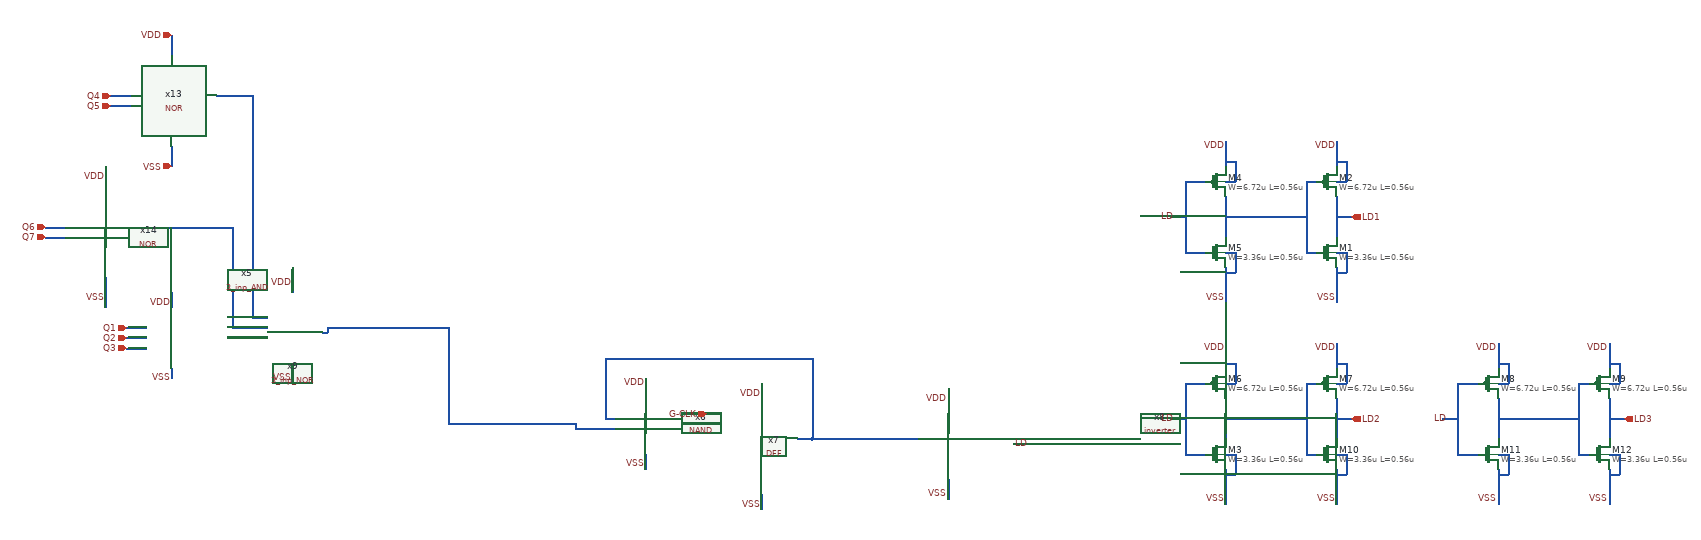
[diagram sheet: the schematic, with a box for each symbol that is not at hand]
v {xschem version=3.1.0 file_version=1.2
}
G {}
K {}
V {}
S {}
E {}
N 2390 1320 2430 1320 {
lab=LD}
N 630 1090 670 1090 {
lab=Q1}
N 1520 1290 1600 1290 {
lab=#net1}
N 1990 1150 1990 1310 {
lab=#net2}
N 1580 1150 1580 1270 {
lab=#net2}
N 1580 1270 1600 1270 {
lab=#net2}
N 1990 1310 2050 1310 {
lab=#net2}
N 1890 1200 1890 1230 {
lab=VDD}
N 1660 1190 1660 1220 {
lab=VDD}
N 1660 1340 1660 1370 {
lab=VSS}
N 1890 1420 1890 1450 {
lab=VSS}
N 1780 1260 1810 1260 {
lab=G-CLK}
N 1320 1280 1510 1280 {
lab=#net1}
N 1520 1280 1520 1290 {
lab=#net1}
N 1510 1280 1520 1280 {
lab=#net1}
N 2050 1310 2200 1310 {
lab=#net2}
N 1730 1280 1810 1280 {
lab=#net3}
N 720 1020 720 1050 {
lab=VDD}
N 720 1170 720 1190 {
lab=VSS}
N 630 1110 670 1110 {
lab=Q2}
N 840 1090 910 1090 {
lab=#net4}
N 680 890 710 890 {
lab=#net4}
N 1270 1110 1270 1280 {
lab=#net1}
N 1270 1280 1320 1280 {
lab=#net1}
N 630 1130 670 1130 {
lab=Q3}
N 1960 1310 1990 1310 {
lab=#net2}
N 1580 1150 1990 1150 {
lab=#net2}
N 2260 1210 2260 1250 {
lab=VDD}
N 2260 1390 2260 1430 {
lab=VSS}
N 1030 1090 1270 1090 {
lab=#net1}
N 1270 1090 1270 1110 {
lab=#net1}
N 1020 1100 1030 1100 {
lab=#net1}
N 1030 1090 1030 1100 {
lab=#net1}
N 880 1070 910 1070 {
lab=#net5}
N 880 630 880 1070 {
lab=#net5}
N 810 630 880 630 {
lab=#net5}
N 960 970 960 1020 {
lab=VDD}
N 960 1160 960 1200 {
lab=VSS}
N 590 770 590 810 {
lab=VDD}
N 590 990 590 1050 {
lab=VSS}
N 720 510 720 550 {
lab=VDD}
N 600 630 640 630 {
lab=Q4}
N 600 650 640 650 {
lab=Q5}
N 720 730 720 770 {
lab=VSS}
N 470 890 510 890 {
lab=Q6}
N 470 910 510 910 {
lab=Q7}
N 2730 800 2730 940 {
lab=LD}
N 2730 940 2770 940 {
lab=LD}
N 2730 800 2770 800 {
lab=LD}
N 2810 830 2810 910 {
lab=#net6}
N 2810 970 2810 1000 {
lab=VSS}
N 2810 740 2810 770 {
lab=VDD}
N 2810 870 2840 870 {
lab=#net6}
N 2700 870 2730 870 {
lab=LD}
N 2810 800 2830 800 {
lab=VDD}
N 2830 760 2830 800 {
lab=VDD}
N 2810 760 2830 760 {
lab=VDD}
N 2810 940 2830 940 {
lab=VSS}
N 2830 940 2830 980 {
lab=VSS}
N 2810 980 2830 980 {
lab=VSS}
N 2810 720 2810 740 {
lab=VDD}
N 2810 1000 2810 1040 {
lab=VSS}
N 3030 830 3030 910 {
lab=LD1}
N 3030 970 3030 1000 {
lab=VSS}
N 3030 740 3030 770 {
lab=VDD}
N 3030 870 3060 870 {
lab=LD1}
N 3030 800 3050 800 {
lab=VDD}
N 3050 760 3050 800 {
lab=VDD}
N 3030 760 3050 760 {
lab=VDD}
N 3030 940 3050 940 {
lab=VSS}
N 3050 940 3050 980 {
lab=VSS}
N 3030 980 3050 980 {
lab=VSS}
N 3030 720 3030 740 {
lab=VDD}
N 3030 1000 3030 1040 {
lab=VSS}
N 2970 800 2990 800 {
lab=#net6}
N 2970 800 2970 940 {
lab=#net6}
N 2970 940 2990 940 {
lab=#net6}
N 2840 870 2970 870 {
lab=#net6}
N 2730 1200 2730 1340 {
lab=LD}
N 2730 1340 2770 1340 {
lab=LD}
N 2730 1200 2770 1200 {
lab=LD}
N 2810 1230 2810 1310 {
lab=#net7}
N 2810 1370 2810 1400 {
lab=VSS}
N 2810 1140 2810 1170 {
lab=VDD}
N 2810 1270 2840 1270 {
lab=#net7}
N 2700 1270 2730 1270 {
lab=LD}
N 2810 1200 2830 1200 {
lab=VDD}
N 2830 1160 2830 1200 {
lab=VDD}
N 2810 1160 2830 1160 {
lab=VDD}
N 2810 1340 2830 1340 {
lab=VSS}
N 2830 1340 2830 1380 {
lab=VSS}
N 2810 1380 2830 1380 {
lab=VSS}
N 2810 1120 2810 1140 {
lab=VDD}
N 2810 1400 2810 1440 {
lab=VSS}
N 3030 1230 3030 1310 {
lab=LD2}
N 3030 1370 3030 1400 {
lab=VSS}
N 3030 1140 3030 1170 {
lab=VDD}
N 3030 1270 3060 1270 {
lab=LD2}
N 3030 1200 3050 1200 {
lab=VDD}
N 3050 1160 3050 1200 {
lab=VDD}
N 3030 1160 3050 1160 {
lab=VDD}
N 3030 1340 3050 1340 {
lab=VSS}
N 3050 1340 3050 1380 {
lab=VSS}
N 3030 1380 3050 1380 {
lab=VSS}
N 3030 1120 3030 1140 {
lab=VDD}
N 3030 1400 3030 1440 {
lab=VSS}
N 2970 1200 2990 1200 {
lab=#net7}
N 2970 1200 2970 1340 {
lab=#net7}
N 2970 1340 2990 1340 {
lab=#net7}
N 2840 1270 2970 1270 {
lab=#net7}
N 3270 1200 3270 1340 {
lab=LD}
N 3270 1340 3310 1340 {
lab=LD}
N 3270 1200 3310 1200 {
lab=LD}
N 3350 1230 3350 1310 {
lab=#net8}
N 3350 1370 3350 1400 {
lab=VSS}
N 3350 1140 3350 1170 {
lab=VDD}
N 3350 1270 3380 1270 {
lab=#net8}
N 3240 1270 3270 1270 {
lab=LD}
N 3350 1200 3370 1200 {
lab=VDD}
N 3370 1160 3370 1200 {
lab=VDD}
N 3350 1160 3370 1160 {
lab=VDD}
N 3350 1340 3370 1340 {
lab=VSS}
N 3370 1340 3370 1380 {
lab=VSS}
N 3350 1380 3370 1380 {
lab=VSS}
N 3350 1120 3350 1140 {
lab=VDD}
N 3350 1400 3350 1440 {
lab=VSS}
N 3570 1230 3570 1310 {
lab=LD3}
N 3570 1370 3570 1400 {
lab=VSS}
N 3570 1140 3570 1170 {
lab=VDD}
N 3570 1270 3600 1270 {
lab=LD3}
N 3570 1200 3590 1200 {
lab=VDD}
N 3590 1160 3590 1200 {
lab=VDD}
N 3570 1160 3590 1160 {
lab=VDD}
N 3570 1340 3590 1340 {
lab=VSS}
N 3590 1340 3590 1380 {
lab=VSS}
N 3570 1380 3590 1380 {
lab=VSS}
N 3570 1120 3570 1140 {
lab=VDD}
N 3570 1400 3570 1440 {
lab=VSS}
N 3510 1200 3530 1200 {
lab=#net8}
N 3510 1200 3510 1340 {
lab=#net8}
N 3510 1340 3530 1340 {
lab=#net8}
N 3380 1270 3510 1270 {
lab=#net8}
N 830 1110 910 1110 {
lab=#net9}
N 710 890 830 890 {
lab=#net4}
N 830 890 840 890 {
lab=#net4}
N 840 890 840 960 {
lab=#net4}
N 840 960 840 1090 {
lab=#net4}
C {devices/lab_wire.sym} 1660 1200 0 0 {name=p8 sig_type=std_logic lab=VDD}
C {devices/lab_wire.sym} 1890 1220 0 0 {name=p9 sig_type=std_logic lab=VDD}
C {devices/lab_wire.sym} 1660 1360 0 0 {name=p12 sig_type=std_logic lab=VSS}
C {devices/lab_wire.sym} 1890 1440 0 0 {name=p13 sig_type=std_logic lab=VSS}
C {NAND.sym} 1750 1290 0 0 {name=x6}
C {devices/lab_wire.sym} 720 1190 0 0 {name=p44 sig_type=std_logic lab=VSS}
C {devices/lab_wire.sym} 720 1040 0 0 {name=p45 sig_type=std_logic lab=VDD}
C {3_inp_NOR.sym} 1040 1210 0 0 {name=x9}
C {DFF.sym} 1960 1280 0 0 {name=x7}
C {devices/lab_wire.sym} 2260 1230 0 0 {name=p59 sig_type=std_logic lab=VDD}
C {devices/lab_wire.sym} 2260 1420 0 0 {name=p60 sig_type=std_logic lab=VSS}
C {inverter.sym} 2350 1330 0 0 {name=x8}
C {3_inp_AND.sym} 1060 1090 0 0 {name=x5}
C {devices/lab_wire.sym} 960 1000 0 0 {name=p47 sig_type=std_logic lab=VDD}
C {devices/lab_wire.sym} 960 1190 0 0 {name=p48 sig_type=std_logic lab=VSS}
C {NOR.sym} 790 650 0 0 {name=x13}
C {NOR.sym} 660 910 0 0 {name=x14}
C {devices/lab_wire.sym} 590 790 0 0 {name=p75 sig_type=std_logic lab=VDD}
C {devices/lab_wire.sym} 590 1030 0 0 {name=p76 sig_type=std_logic lab=VSS}
C {symbols/pfet_03v3.sym} 2790 800 0 0 {name=M4
L=0.56u
W=6.72u
nf=1
m=1
ad="'int((nf+1)/2) * W/nf * 0.18u'"
pd="'2*int((nf+1)/2) * (W/nf + 0.18u)'"
as="'int((nf+2)/2) * W/nf * 0.18u'"
ps="'2*int((nf+2)/2) * (W/nf + 0.18u)'"
nrd="'0.18u / W'" nrs="'0.18u / W'"
sa=0 sb=0 sd=0
model=pfet_03v3
spiceprefix=X
}
C {symbols/nfet_03v3.sym} 2790 940 0 0 {name=M5
L=0.56u
W=3.36u
nf=1
m=1
ad="'int((nf+1)/2) * W/nf * 0.18u'"
pd="'2*int((nf+1)/2) * (W/nf + 0.18u)'"
as="'int((nf+2)/2) * W/nf * 0.18u'"
ps="'2*int((nf+2)/2) * (W/nf + 0.18u)'"
nrd="'0.18u / W'" nrs="'0.18u / W'"
sa=0 sb=0 sd=0
model=nfet_03v3
spiceprefix=X
}
C {devices/lab_wire.sym} 2810 730 0 0 {name=p82 sig_type=std_logic lab=VDD}
C {devices/lab_wire.sym} 2810 1030 0 0 {name=p83 sig_type=std_logic lab=VSS}
C {devices/lab_wire.sym} 2710 870 0 0 {name=p84 sig_type=std_logic lab=LD}
C {devices/lab_wire.sym} 3030 730 0 0 {name=p81 sig_type=std_logic lab=VDD}
C {devices/lab_wire.sym} 3030 1030 0 0 {name=p85 sig_type=std_logic lab=VSS}
C {devices/lab_wire.sym} 2810 1130 0 0 {name=p87 sig_type=std_logic lab=VDD}
C {devices/lab_wire.sym} 2810 1430 0 0 {name=p88 sig_type=std_logic lab=VSS}
C {devices/lab_wire.sym} 2710 1270 0 0 {name=p89 sig_type=std_logic lab=LD}
C {devices/lab_wire.sym} 3030 1130 0 0 {name=p90 sig_type=std_logic lab=VDD}
C {devices/lab_wire.sym} 3030 1430 0 0 {name=p91 sig_type=std_logic lab=VSS}
C {devices/lab_wire.sym} 3350 1130 0 0 {name=p93 sig_type=std_logic lab=VDD}
C {devices/lab_wire.sym} 3350 1430 0 0 {name=p94 sig_type=std_logic lab=VSS}
C {devices/lab_wire.sym} 3250 1270 0 0 {name=p95 sig_type=std_logic lab=LD}
C {devices/lab_wire.sym} 3570 1130 0 0 {name=p96 sig_type=std_logic lab=VDD}
C {devices/lab_wire.sym} 3570 1430 0 0 {name=p97 sig_type=std_logic lab=VSS}
C {symbols/nfet_03v3.sym} 3010 940 0 0 {name=M1
L=0.56u
W=3.36u
nf=1
m=1
ad="'int((nf+1)/2) * W/nf * 0.18u'"
pd="'2*int((nf+1)/2) * (W/nf + 0.18u)'"
as="'int((nf+2)/2) * W/nf * 0.18u'"
ps="'2*int((nf+2)/2) * (W/nf + 0.18u)'"
nrd="'0.18u / W'" nrs="'0.18u / W'"
sa=0 sb=0 sd=0
model=nfet_03v3
spiceprefix=X
}
C {symbols/pfet_03v3.sym} 3010 800 0 0 {name=M2
L=0.56u
W=6.72u
nf=1
m=1
ad="'int((nf+1)/2) * W/nf * 0.18u'"
pd="'2*int((nf+1)/2) * (W/nf + 0.18u)'"
as="'int((nf+2)/2) * W/nf * 0.18u'"
ps="'2*int((nf+2)/2) * (W/nf + 0.18u)'"
nrd="'0.18u / W'" nrs="'0.18u / W'"
sa=0 sb=0 sd=0
model=pfet_03v3
spiceprefix=X
}
C {symbols/nfet_03v3.sym} 2790 1340 0 0 {name=M3
L=0.56u
W=3.36u
nf=1
m=1
ad="'int((nf+1)/2) * W/nf * 0.18u'"
pd="'2*int((nf+1)/2) * (W/nf + 0.18u)'"
as="'int((nf+2)/2) * W/nf * 0.18u'"
ps="'2*int((nf+2)/2) * (W/nf + 0.18u)'"
nrd="'0.18u / W'" nrs="'0.18u / W'"
sa=0 sb=0 sd=0
model=nfet_03v3
spiceprefix=X
}
C {symbols/pfet_03v3.sym} 2790 1200 0 0 {name=M6
L=0.56u
W=6.72u
nf=1
m=1
ad="'int((nf+1)/2) * W/nf * 0.18u'"
pd="'2*int((nf+1)/2) * (W/nf + 0.18u)'"
as="'int((nf+2)/2) * W/nf * 0.18u'"
ps="'2*int((nf+2)/2) * (W/nf + 0.18u)'"
nrd="'0.18u / W'" nrs="'0.18u / W'"
sa=0 sb=0 sd=0
model=pfet_03v3
spiceprefix=X
}
C {symbols/pfet_03v3.sym} 3010 1200 0 0 {name=M7
L=0.56u
W=6.72u
nf=1
m=1
ad="'int((nf+1)/2) * W/nf * 0.18u'"
pd="'2*int((nf+1)/2) * (W/nf + 0.18u)'"
as="'int((nf+2)/2) * W/nf * 0.18u'"
ps="'2*int((nf+2)/2) * (W/nf + 0.18u)'"
nrd="'0.18u / W'" nrs="'0.18u / W'"
sa=0 sb=0 sd=0
model=pfet_03v3
spiceprefix=X
}
C {symbols/pfet_03v3.sym} 3330 1200 0 0 {name=M8
L=0.56u
W=6.72u
nf=1
m=1
ad="'int((nf+1)/2) * W/nf * 0.18u'"
pd="'2*int((nf+1)/2) * (W/nf + 0.18u)'"
as="'int((nf+2)/2) * W/nf * 0.18u'"
ps="'2*int((nf+2)/2) * (W/nf + 0.18u)'"
nrd="'0.18u / W'" nrs="'0.18u / W'"
sa=0 sb=0 sd=0
model=pfet_03v3
spiceprefix=X
}
C {symbols/pfet_03v3.sym} 3550 1200 0 0 {name=M9
L=0.56u
W=6.72u
nf=1
m=1
ad="'int((nf+1)/2) * W/nf * 0.18u'"
pd="'2*int((nf+1)/2) * (W/nf + 0.18u)'"
as="'int((nf+2)/2) * W/nf * 0.18u'"
ps="'2*int((nf+2)/2) * (W/nf + 0.18u)'"
nrd="'0.18u / W'" nrs="'0.18u / W'"
sa=0 sb=0 sd=0
model=pfet_03v3
spiceprefix=X
}
C {symbols/nfet_03v3.sym} 3010 1340 0 0 {name=M10
L=0.56u
W=3.36u
nf=1
m=1
ad="'int((nf+1)/2) * W/nf * 0.18u'"
pd="'2*int((nf+1)/2) * (W/nf + 0.18u)'"
as="'int((nf+2)/2) * W/nf * 0.18u'"
ps="'2*int((nf+2)/2) * (W/nf + 0.18u)'"
nrd="'0.18u / W'" nrs="'0.18u / W'"
sa=0 sb=0 sd=0
model=nfet_03v3
spiceprefix=X
}
C {symbols/nfet_03v3.sym} 3330 1340 0 0 {name=M11
L=0.56u
W=3.36u
nf=1
m=1
ad="'int((nf+1)/2) * W/nf * 0.18u'"
pd="'2*int((nf+1)/2) * (W/nf + 0.18u)'"
as="'int((nf+2)/2) * W/nf * 0.18u'"
ps="'2*int((nf+2)/2) * (W/nf + 0.18u)'"
nrd="'0.18u / W'" nrs="'0.18u / W'"
sa=0 sb=0 sd=0
model=nfet_03v3
spiceprefix=X
}
C {symbols/nfet_03v3.sym} 3550 1340 0 0 {name=M12
L=0.56u
W=3.36u
nf=1
m=1
ad="'int((nf+1)/2) * W/nf * 0.18u'"
pd="'2*int((nf+1)/2) * (W/nf + 0.18u)'"
as="'int((nf+2)/2) * W/nf * 0.18u'"
ps="'2*int((nf+2)/2) * (W/nf + 0.18u)'"
nrd="'0.18u / W'" nrs="'0.18u / W'"
sa=0 sb=0 sd=0
model=nfet_03v3
spiceprefix=X
}
C {devices/lab_wire.sym} 2420 1320 0 0 {name=p1 sig_type=std_logic lab=LD}
C {devices/ipin.sym} 630 1090 0 0 {name=p2 lab=Q1}
C {devices/ipin.sym} 630 1110 0 0 {name=p3 lab=Q2}
C {devices/ipin.sym} 630 1130 0 0 {name=p4 lab=Q3}
C {devices/ipin.sym} 470 890 0 0 {name=p5 lab=Q6}
C {devices/ipin.sym} 470 910 0 0 {name=p7 lab=Q7}
C {devices/ipin.sym} 600 630 0 0 {name=p10 lab=Q4}
C {devices/ipin.sym} 600 650 0 0 {name=p11 lab=Q5}
C {devices/iopin.sym} 720 510 3 0 {name=p6 lab=VDD}
C {devices/iopin.sym} 720 770 1 0 {name=p14 lab=VSS}
C {devices/opin.sym} 3060 870 0 0 {name=p15 lab=LD1}
C {devices/opin.sym} 3060 1270 0 0 {name=p16 lab=LD2}
C {devices/opin.sym} 3600 1270 0 0 {name=p17 lab=LD3}
C {devices/ipin.sym} 1780 1260 0 0 {name=p18 lab=G-CLK}
